VERSION 5.7 ;
BUSBITCHARS "[]" ;
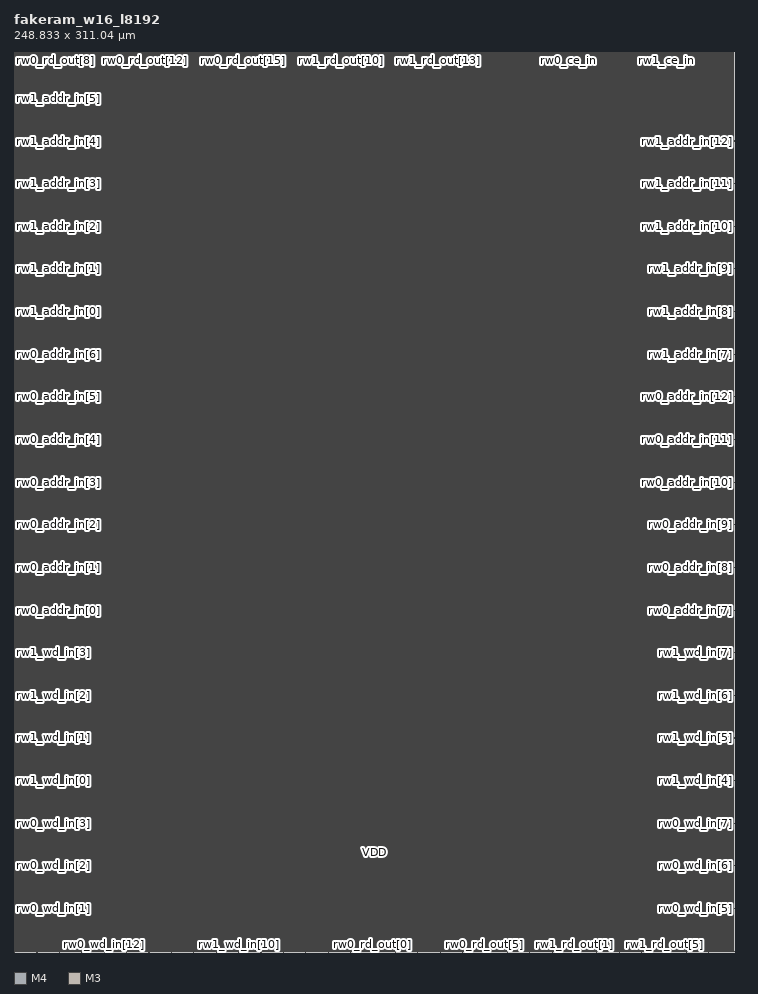
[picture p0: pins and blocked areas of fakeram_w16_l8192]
MACRO fakeram_w16_l8192
  FOREIGN fakeram_w16_l8192 0 0 ;
  SYMMETRY X Y R90 ;
  SIZE 248.833 BY 311.040 ;
  CLASS BLOCK ;
  PIN rw0_wd_in[0]
    DIRECTION INPUT ;
    USE SIGNAL ;
    SHAPE ABUTMENT ;
    PORT
      LAYER M4 ;
      RECT 0.000 0.276 0.072 0.300 ;
    END
  END rw0_wd_in[0]
  PIN rw0_wd_in[1]
    DIRECTION INPUT ;
    USE SIGNAL ;
    SHAPE ABUTMENT ;
    PORT
      LAYER M4 ;
      RECT 0.000 15.012 0.072 15.036 ;
    END
  END rw0_wd_in[1]
  PIN rw0_wd_in[2]
    DIRECTION INPUT ;
    USE SIGNAL ;
    SHAPE ABUTMENT ;
    PORT
      LAYER M4 ;
      RECT 0.000 29.748 0.072 29.772 ;
    END
  END rw0_wd_in[2]
  PIN rw0_wd_in[3]
    DIRECTION INPUT ;
    USE SIGNAL ;
    SHAPE ABUTMENT ;
    PORT
      LAYER M4 ;
      RECT 0.000 44.484 0.072 44.508 ;
    END
  END rw0_wd_in[3]
  PIN rw0_wd_in[4]
    DIRECTION INPUT ;
    USE SIGNAL ;
    SHAPE ABUTMENT ;
    PORT
      LAYER M4 ;
      RECT 248.761 0.276 248.833 0.300 ;
    END
  END rw0_wd_in[4]
  PIN rw0_wd_in[5]
    DIRECTION INPUT ;
    USE SIGNAL ;
    SHAPE ABUTMENT ;
    PORT
      LAYER M4 ;
      RECT 248.761 15.012 248.833 15.036 ;
    END
  END rw0_wd_in[5]
  PIN rw0_wd_in[6]
    DIRECTION INPUT ;
    USE SIGNAL ;
    SHAPE ABUTMENT ;
    PORT
      LAYER M4 ;
      RECT 248.761 29.748 248.833 29.772 ;
    END
  END rw0_wd_in[6]
  PIN rw0_wd_in[7]
    DIRECTION INPUT ;
    USE SIGNAL ;
    SHAPE ABUTMENT ;
    PORT
      LAYER M4 ;
      RECT 248.761 44.484 248.833 44.508 ;
    END
  END rw0_wd_in[7]
  PIN rw0_wd_in[8]
    DIRECTION INPUT ;
    USE SIGNAL ;
    SHAPE ABUTMENT ;
    PORT
      LAYER M3 ;
      RECT 0.207 0.000 0.225 0.054 ;
    END
  END rw0_wd_in[8]
  PIN rw0_wd_in[9]
    DIRECTION INPUT ;
    USE SIGNAL ;
    SHAPE ABUTMENT ;
    PORT
      LAYER M3 ;
      RECT 7.947 0.000 7.965 0.054 ;
    END
  END rw0_wd_in[9]
  PIN rw0_wd_in[10]
    DIRECTION INPUT ;
    USE SIGNAL ;
    SHAPE ABUTMENT ;
    PORT
      LAYER M3 ;
      RECT 15.687 0.000 15.705 0.054 ;
    END
  END rw0_wd_in[10]
  PIN rw0_wd_in[11]
    DIRECTION INPUT ;
    USE SIGNAL ;
    SHAPE ABUTMENT ;
    PORT
      LAYER M3 ;
      RECT 23.427 0.000 23.445 0.054 ;
    END
  END rw0_wd_in[11]
  PIN rw0_wd_in[12]
    DIRECTION INPUT ;
    USE SIGNAL ;
    SHAPE ABUTMENT ;
    PORT
      LAYER M3 ;
      RECT 31.167 0.000 31.185 0.054 ;
    END
  END rw0_wd_in[12]
  PIN rw0_wd_in[13]
    DIRECTION INPUT ;
    USE SIGNAL ;
    SHAPE ABUTMENT ;
    PORT
      LAYER M3 ;
      RECT 38.907 0.000 38.925 0.054 ;
    END
  END rw0_wd_in[13]
  PIN rw0_wd_in[14]
    DIRECTION INPUT ;
    USE SIGNAL ;
    SHAPE ABUTMENT ;
    PORT
      LAYER M3 ;
      RECT 46.647 0.000 46.665 0.054 ;
    END
  END rw0_wd_in[14]
  PIN rw0_wd_in[15]
    DIRECTION INPUT ;
    USE SIGNAL ;
    SHAPE ABUTMENT ;
    PORT
      LAYER M3 ;
      RECT 54.387 0.000 54.405 0.054 ;
    END
  END rw0_wd_in[15]
  PIN rw1_wd_in[0]
    DIRECTION INPUT ;
    USE SIGNAL ;
    SHAPE ABUTMENT ;
    PORT
      LAYER M4 ;
      RECT 0.000 59.220 0.072 59.244 ;
    END
  END rw1_wd_in[0]
  PIN rw1_wd_in[1]
    DIRECTION INPUT ;
    USE SIGNAL ;
    SHAPE ABUTMENT ;
    PORT
      LAYER M4 ;
      RECT 0.000 73.956 0.072 73.980 ;
    END
  END rw1_wd_in[1]
  PIN rw1_wd_in[2]
    DIRECTION INPUT ;
    USE SIGNAL ;
    SHAPE ABUTMENT ;
    PORT
      LAYER M4 ;
      RECT 0.000 88.692 0.072 88.716 ;
    END
  END rw1_wd_in[2]
  PIN rw1_wd_in[3]
    DIRECTION INPUT ;
    USE SIGNAL ;
    SHAPE ABUTMENT ;
    PORT
      LAYER M4 ;
      RECT 0.000 103.428 0.072 103.452 ;
    END
  END rw1_wd_in[3]
  PIN rw1_wd_in[4]
    DIRECTION INPUT ;
    USE SIGNAL ;
    SHAPE ABUTMENT ;
    PORT
      LAYER M4 ;
      RECT 248.761 59.220 248.833 59.244 ;
    END
  END rw1_wd_in[4]
  PIN rw1_wd_in[5]
    DIRECTION INPUT ;
    USE SIGNAL ;
    SHAPE ABUTMENT ;
    PORT
      LAYER M4 ;
      RECT 248.761 73.956 248.833 73.980 ;
    END
  END rw1_wd_in[5]
  PIN rw1_wd_in[6]
    DIRECTION INPUT ;
    USE SIGNAL ;
    SHAPE ABUTMENT ;
    PORT
      LAYER M4 ;
      RECT 248.761 88.692 248.833 88.716 ;
    END
  END rw1_wd_in[6]
  PIN rw1_wd_in[7]
    DIRECTION INPUT ;
    USE SIGNAL ;
    SHAPE ABUTMENT ;
    PORT
      LAYER M4 ;
      RECT 248.761 103.428 248.833 103.452 ;
    END
  END rw1_wd_in[7]
  PIN rw1_wd_in[8]
    DIRECTION INPUT ;
    USE SIGNAL ;
    SHAPE ABUTMENT ;
    PORT
      LAYER M3 ;
      RECT 62.127 0.000 62.145 0.054 ;
    END
  END rw1_wd_in[8]
  PIN rw1_wd_in[9]
    DIRECTION INPUT ;
    USE SIGNAL ;
    SHAPE ABUTMENT ;
    PORT
      LAYER M3 ;
      RECT 69.867 0.000 69.885 0.054 ;
    END
  END rw1_wd_in[9]
  PIN rw1_wd_in[10]
    DIRECTION INPUT ;
    USE SIGNAL ;
    SHAPE ABUTMENT ;
    PORT
      LAYER M3 ;
      RECT 77.607 0.000 77.625 0.054 ;
    END
  END rw1_wd_in[10]
  PIN rw1_wd_in[11]
    DIRECTION INPUT ;
    USE SIGNAL ;
    SHAPE ABUTMENT ;
    PORT
      LAYER M3 ;
      RECT 85.347 0.000 85.365 0.054 ;
    END
  END rw1_wd_in[11]
  PIN rw1_wd_in[12]
    DIRECTION INPUT ;
    USE SIGNAL ;
    SHAPE ABUTMENT ;
    PORT
      LAYER M3 ;
      RECT 93.087 0.000 93.105 0.054 ;
    END
  END rw1_wd_in[12]
  PIN rw1_wd_in[13]
    DIRECTION INPUT ;
    USE SIGNAL ;
    SHAPE ABUTMENT ;
    PORT
      LAYER M3 ;
      RECT 100.827 0.000 100.845 0.054 ;
    END
  END rw1_wd_in[13]
  PIN rw1_wd_in[14]
    DIRECTION INPUT ;
    USE SIGNAL ;
    SHAPE ABUTMENT ;
    PORT
      LAYER M3 ;
      RECT 108.567 0.000 108.585 0.054 ;
    END
  END rw1_wd_in[14]
  PIN rw1_wd_in[15]
    DIRECTION INPUT ;
    USE SIGNAL ;
    SHAPE ABUTMENT ;
    PORT
      LAYER M3 ;
      RECT 116.307 0.000 116.325 0.054 ;
    END
  END rw1_wd_in[15]
  PIN rw0_rd_out[0]
    DIRECTION OUTPUT ;
    USE SIGNAL ;
    SHAPE ABUTMENT ;
    PORT
      LAYER M3 ;
      RECT 124.047 0.000 124.065 0.054 ;
    END
  END rw0_rd_out[0]
  PIN rw0_rd_out[1]
    DIRECTION OUTPUT ;
    USE SIGNAL ;
    SHAPE ABUTMENT ;
    PORT
      LAYER M3 ;
      RECT 131.787 0.000 131.805 0.054 ;
    END
  END rw0_rd_out[1]
  PIN rw0_rd_out[2]
    DIRECTION OUTPUT ;
    USE SIGNAL ;
    SHAPE ABUTMENT ;
    PORT
      LAYER M3 ;
      RECT 139.527 0.000 139.545 0.054 ;
    END
  END rw0_rd_out[2]
  PIN rw0_rd_out[3]
    DIRECTION OUTPUT ;
    USE SIGNAL ;
    SHAPE ABUTMENT ;
    PORT
      LAYER M3 ;
      RECT 147.267 0.000 147.285 0.054 ;
    END
  END rw0_rd_out[3]
  PIN rw0_rd_out[4]
    DIRECTION OUTPUT ;
    USE SIGNAL ;
    SHAPE ABUTMENT ;
    PORT
      LAYER M3 ;
      RECT 155.007 0.000 155.025 0.054 ;
    END
  END rw0_rd_out[4]
  PIN rw0_rd_out[5]
    DIRECTION OUTPUT ;
    USE SIGNAL ;
    SHAPE ABUTMENT ;
    PORT
      LAYER M3 ;
      RECT 162.747 0.000 162.765 0.054 ;
    END
  END rw0_rd_out[5]
  PIN rw0_rd_out[6]
    DIRECTION OUTPUT ;
    USE SIGNAL ;
    SHAPE ABUTMENT ;
    PORT
      LAYER M3 ;
      RECT 170.487 0.000 170.505 0.054 ;
    END
  END rw0_rd_out[6]
  PIN rw0_rd_out[7]
    DIRECTION OUTPUT ;
    USE SIGNAL ;
    SHAPE ABUTMENT ;
    PORT
      LAYER M3 ;
      RECT 178.227 0.000 178.245 0.054 ;
    END
  END rw0_rd_out[7]
  PIN rw0_rd_out[8]
    DIRECTION OUTPUT ;
    USE SIGNAL ;
    SHAPE ABUTMENT ;
    PORT
      LAYER M3 ;
      RECT 0.207 310.986 0.225 311.040 ;
    END
  END rw0_rd_out[8]
  PIN rw0_rd_out[9]
    DIRECTION OUTPUT ;
    USE SIGNAL ;
    SHAPE ABUTMENT ;
    PORT
      LAYER M3 ;
      RECT 11.475 310.986 11.493 311.040 ;
    END
  END rw0_rd_out[9]
  PIN rw0_rd_out[10]
    DIRECTION OUTPUT ;
    USE SIGNAL ;
    SHAPE ABUTMENT ;
    PORT
      LAYER M3 ;
      RECT 22.743 310.986 22.761 311.040 ;
    END
  END rw0_rd_out[10]
  PIN rw0_rd_out[11]
    DIRECTION OUTPUT ;
    USE SIGNAL ;
    SHAPE ABUTMENT ;
    PORT
      LAYER M3 ;
      RECT 34.011 310.986 34.029 311.040 ;
    END
  END rw0_rd_out[11]
  PIN rw0_rd_out[12]
    DIRECTION OUTPUT ;
    USE SIGNAL ;
    SHAPE ABUTMENT ;
    PORT
      LAYER M3 ;
      RECT 45.279 310.986 45.297 311.040 ;
    END
  END rw0_rd_out[12]
  PIN rw0_rd_out[13]
    DIRECTION OUTPUT ;
    USE SIGNAL ;
    SHAPE ABUTMENT ;
    PORT
      LAYER M3 ;
      RECT 56.547 310.986 56.565 311.040 ;
    END
  END rw0_rd_out[13]
  PIN rw0_rd_out[14]
    DIRECTION OUTPUT ;
    USE SIGNAL ;
    SHAPE ABUTMENT ;
    PORT
      LAYER M3 ;
      RECT 67.815 310.986 67.833 311.040 ;
    END
  END rw0_rd_out[14]
  PIN rw0_rd_out[15]
    DIRECTION OUTPUT ;
    USE SIGNAL ;
    SHAPE ABUTMENT ;
    PORT
      LAYER M3 ;
      RECT 79.083 310.986 79.101 311.040 ;
    END
  END rw0_rd_out[15]
  PIN rw1_rd_out[0]
    DIRECTION OUTPUT ;
    USE SIGNAL ;
    SHAPE ABUTMENT ;
    PORT
      LAYER M3 ;
      RECT 185.967 0.000 185.985 0.054 ;
    END
  END rw1_rd_out[0]
  PIN rw1_rd_out[1]
    DIRECTION OUTPUT ;
    USE SIGNAL ;
    SHAPE ABUTMENT ;
    PORT
      LAYER M3 ;
      RECT 193.707 0.000 193.725 0.054 ;
    END
  END rw1_rd_out[1]
  PIN rw1_rd_out[2]
    DIRECTION OUTPUT ;
    USE SIGNAL ;
    SHAPE ABUTMENT ;
    PORT
      LAYER M3 ;
      RECT 201.447 0.000 201.465 0.054 ;
    END
  END rw1_rd_out[2]
  PIN rw1_rd_out[3]
    DIRECTION OUTPUT ;
    USE SIGNAL ;
    SHAPE ABUTMENT ;
    PORT
      LAYER M3 ;
      RECT 209.187 0.000 209.205 0.054 ;
    END
  END rw1_rd_out[3]
  PIN rw1_rd_out[4]
    DIRECTION OUTPUT ;
    USE SIGNAL ;
    SHAPE ABUTMENT ;
    PORT
      LAYER M3 ;
      RECT 216.927 0.000 216.945 0.054 ;
    END
  END rw1_rd_out[4]
  PIN rw1_rd_out[5]
    DIRECTION OUTPUT ;
    USE SIGNAL ;
    SHAPE ABUTMENT ;
    PORT
      LAYER M3 ;
      RECT 224.667 0.000 224.685 0.054 ;
    END
  END rw1_rd_out[5]
  PIN rw1_rd_out[6]
    DIRECTION OUTPUT ;
    USE SIGNAL ;
    SHAPE ABUTMENT ;
    PORT
      LAYER M3 ;
      RECT 232.407 0.000 232.425 0.054 ;
    END
  END rw1_rd_out[6]
  PIN rw1_rd_out[7]
    DIRECTION OUTPUT ;
    USE SIGNAL ;
    SHAPE ABUTMENT ;
    PORT
      LAYER M3 ;
      RECT 240.147 0.000 240.165 0.054 ;
    END
  END rw1_rd_out[7]
  PIN rw1_rd_out[8]
    DIRECTION OUTPUT ;
    USE SIGNAL ;
    SHAPE ABUTMENT ;
    PORT
      LAYER M3 ;
      RECT 90.351 310.986 90.369 311.040 ;
    END
  END rw1_rd_out[8]
  PIN rw1_rd_out[9]
    DIRECTION OUTPUT ;
    USE SIGNAL ;
    SHAPE ABUTMENT ;
    PORT
      LAYER M3 ;
      RECT 101.619 310.986 101.637 311.040 ;
    END
  END rw1_rd_out[9]
  PIN rw1_rd_out[10]
    DIRECTION OUTPUT ;
    USE SIGNAL ;
    SHAPE ABUTMENT ;
    PORT
      LAYER M3 ;
      RECT 112.887 310.986 112.905 311.040 ;
    END
  END rw1_rd_out[10]
  PIN rw1_rd_out[11]
    DIRECTION OUTPUT ;
    USE SIGNAL ;
    SHAPE ABUTMENT ;
    PORT
      LAYER M3 ;
      RECT 124.155 310.986 124.173 311.040 ;
    END
  END rw1_rd_out[11]
  PIN rw1_rd_out[12]
    DIRECTION OUTPUT ;
    USE SIGNAL ;
    SHAPE ABUTMENT ;
    PORT
      LAYER M3 ;
      RECT 135.423 310.986 135.441 311.040 ;
    END
  END rw1_rd_out[12]
  PIN rw1_rd_out[13]
    DIRECTION OUTPUT ;
    USE SIGNAL ;
    SHAPE ABUTMENT ;
    PORT
      LAYER M3 ;
      RECT 146.691 310.986 146.709 311.040 ;
    END
  END rw1_rd_out[13]
  PIN rw1_rd_out[14]
    DIRECTION OUTPUT ;
    USE SIGNAL ;
    SHAPE ABUTMENT ;
    PORT
      LAYER M3 ;
      RECT 157.959 310.986 157.977 311.040 ;
    END
  END rw1_rd_out[14]
  PIN rw1_rd_out[15]
    DIRECTION OUTPUT ;
    USE SIGNAL ;
    SHAPE ABUTMENT ;
    PORT
      LAYER M3 ;
      RECT 169.227 310.986 169.245 311.040 ;
    END
  END rw1_rd_out[15]
  PIN rw0_addr_in[0]
    DIRECTION INPUT ;
    USE SIGNAL ;
    SHAPE ABUTMENT ;
    PORT
      LAYER M4 ;
      RECT 0.000 118.164 0.072 118.188 ;
    END
  END rw0_addr_in[0]
  PIN rw0_addr_in[1]
    DIRECTION INPUT ;
    USE SIGNAL ;
    SHAPE ABUTMENT ;
    PORT
      LAYER M4 ;
      RECT 0.000 132.900 0.072 132.924 ;
    END
  END rw0_addr_in[1]
  PIN rw0_addr_in[2]
    DIRECTION INPUT ;
    USE SIGNAL ;
    SHAPE ABUTMENT ;
    PORT
      LAYER M4 ;
      RECT 0.000 147.636 0.072 147.660 ;
    END
  END rw0_addr_in[2]
  PIN rw0_addr_in[3]
    DIRECTION INPUT ;
    USE SIGNAL ;
    SHAPE ABUTMENT ;
    PORT
      LAYER M4 ;
      RECT 0.000 162.372 0.072 162.396 ;
    END
  END rw0_addr_in[3]
  PIN rw0_addr_in[4]
    DIRECTION INPUT ;
    USE SIGNAL ;
    SHAPE ABUTMENT ;
    PORT
      LAYER M4 ;
      RECT 0.000 177.108 0.072 177.132 ;
    END
  END rw0_addr_in[4]
  PIN rw0_addr_in[5]
    DIRECTION INPUT ;
    USE SIGNAL ;
    SHAPE ABUTMENT ;
    PORT
      LAYER M4 ;
      RECT 0.000 191.844 0.072 191.868 ;
    END
  END rw0_addr_in[5]
  PIN rw0_addr_in[6]
    DIRECTION INPUT ;
    USE SIGNAL ;
    SHAPE ABUTMENT ;
    PORT
      LAYER M4 ;
      RECT 0.000 206.580 0.072 206.604 ;
    END
  END rw0_addr_in[6]
  PIN rw0_addr_in[7]
    DIRECTION INPUT ;
    USE SIGNAL ;
    SHAPE ABUTMENT ;
    PORT
      LAYER M4 ;
      RECT 248.761 118.164 248.833 118.188 ;
    END
  END rw0_addr_in[7]
  PIN rw0_addr_in[8]
    DIRECTION INPUT ;
    USE SIGNAL ;
    SHAPE ABUTMENT ;
    PORT
      LAYER M4 ;
      RECT 248.761 132.900 248.833 132.924 ;
    END
  END rw0_addr_in[8]
  PIN rw0_addr_in[9]
    DIRECTION INPUT ;
    USE SIGNAL ;
    SHAPE ABUTMENT ;
    PORT
      LAYER M4 ;
      RECT 248.761 147.636 248.833 147.660 ;
    END
  END rw0_addr_in[9]
  PIN rw0_addr_in[10]
    DIRECTION INPUT ;
    USE SIGNAL ;
    SHAPE ABUTMENT ;
    PORT
      LAYER M4 ;
      RECT 248.761 162.372 248.833 162.396 ;
    END
  END rw0_addr_in[10]
  PIN rw0_addr_in[11]
    DIRECTION INPUT ;
    USE SIGNAL ;
    SHAPE ABUTMENT ;
    PORT
      LAYER M4 ;
      RECT 248.761 177.108 248.833 177.132 ;
    END
  END rw0_addr_in[11]
  PIN rw0_addr_in[12]
    DIRECTION INPUT ;
    USE SIGNAL ;
    SHAPE ABUTMENT ;
    PORT
      LAYER M4 ;
      RECT 248.761 191.844 248.833 191.868 ;
    END
  END rw0_addr_in[12]
  PIN rw1_addr_in[0]
    DIRECTION INPUT ;
    USE SIGNAL ;
    SHAPE ABUTMENT ;
    PORT
      LAYER M4 ;
      RECT 0.000 221.316 0.072 221.340 ;
    END
  END rw1_addr_in[0]
  PIN rw1_addr_in[1]
    DIRECTION INPUT ;
    USE SIGNAL ;
    SHAPE ABUTMENT ;
    PORT
      LAYER M4 ;
      RECT 0.000 236.052 0.072 236.076 ;
    END
  END rw1_addr_in[1]
  PIN rw1_addr_in[2]
    DIRECTION INPUT ;
    USE SIGNAL ;
    SHAPE ABUTMENT ;
    PORT
      LAYER M4 ;
      RECT 0.000 250.788 0.072 250.812 ;
    END
  END rw1_addr_in[2]
  PIN rw1_addr_in[3]
    DIRECTION INPUT ;
    USE SIGNAL ;
    SHAPE ABUTMENT ;
    PORT
      LAYER M4 ;
      RECT 0.000 265.524 0.072 265.548 ;
    END
  END rw1_addr_in[3]
  PIN rw1_addr_in[4]
    DIRECTION INPUT ;
    USE SIGNAL ;
    SHAPE ABUTMENT ;
    PORT
      LAYER M4 ;
      RECT 0.000 280.260 0.072 280.284 ;
    END
  END rw1_addr_in[4]
  PIN rw1_addr_in[5]
    DIRECTION INPUT ;
    USE SIGNAL ;
    SHAPE ABUTMENT ;
    PORT
      LAYER M4 ;
      RECT 0.000 294.996 0.072 295.020 ;
    END
  END rw1_addr_in[5]
  PIN rw1_addr_in[6]
    DIRECTION INPUT ;
    USE SIGNAL ;
    SHAPE ABUTMENT ;
    PORT
      LAYER M4 ;
      RECT 0.000 309.732 0.072 309.756 ;
    END
  END rw1_addr_in[6]
  PIN rw1_addr_in[7]
    DIRECTION INPUT ;
    USE SIGNAL ;
    SHAPE ABUTMENT ;
    PORT
      LAYER M4 ;
      RECT 248.761 206.580 248.833 206.604 ;
    END
  END rw1_addr_in[7]
  PIN rw1_addr_in[8]
    DIRECTION INPUT ;
    USE SIGNAL ;
    SHAPE ABUTMENT ;
    PORT
      LAYER M4 ;
      RECT 248.761 221.316 248.833 221.340 ;
    END
  END rw1_addr_in[8]
  PIN rw1_addr_in[9]
    DIRECTION INPUT ;
    USE SIGNAL ;
    SHAPE ABUTMENT ;
    PORT
      LAYER M4 ;
      RECT 248.761 236.052 248.833 236.076 ;
    END
  END rw1_addr_in[9]
  PIN rw1_addr_in[10]
    DIRECTION INPUT ;
    USE SIGNAL ;
    SHAPE ABUTMENT ;
    PORT
      LAYER M4 ;
      RECT 248.761 250.788 248.833 250.812 ;
    END
  END rw1_addr_in[10]
  PIN rw1_addr_in[11]
    DIRECTION INPUT ;
    USE SIGNAL ;
    SHAPE ABUTMENT ;
    PORT
      LAYER M4 ;
      RECT 248.761 265.524 248.833 265.548 ;
    END
  END rw1_addr_in[11]
  PIN rw1_addr_in[12]
    DIRECTION INPUT ;
    USE SIGNAL ;
    SHAPE ABUTMENT ;
    PORT
      LAYER M4 ;
      RECT 248.761 280.260 248.833 280.284 ;
    END
  END rw1_addr_in[12]
  PIN rw0_we_in
    DIRECTION INPUT ;
    USE SIGNAL ;
    SHAPE ABUTMENT ;
    PORT
      LAYER M3 ;
      RECT 180.495 310.986 180.513 311.040 ;
    END
  END rw0_we_in
  PIN rw0_ce_in
    DIRECTION INPUT ;
    USE SIGNAL ;
    SHAPE ABUTMENT ;
    PORT
      LAYER M3 ;
      RECT 191.763 310.986 191.781 311.040 ;
    END
  END rw0_ce_in
  PIN rw0_clk
    DIRECTION INPUT ;
    USE SIGNAL ;
    SHAPE ABUTMENT ;
    PORT
      LAYER M3 ;
      RECT 203.031 310.986 203.049 311.040 ;
    END
  END rw0_clk
  PIN rw1_we_in
    DIRECTION INPUT ;
    USE SIGNAL ;
    SHAPE ABUTMENT ;
    PORT
      LAYER M3 ;
      RECT 214.299 310.986 214.317 311.040 ;
    END
  END rw1_we_in
  PIN rw1_ce_in
    DIRECTION INPUT ;
    USE SIGNAL ;
    SHAPE ABUTMENT ;
    PORT
      LAYER M3 ;
      RECT 225.567 310.986 225.585 311.040 ;
    END
  END rw1_ce_in
  PIN rw1_clk
    DIRECTION INPUT ;
    USE SIGNAL ;
    SHAPE ABUTMENT ;
    PORT
      LAYER M3 ;
      RECT 236.835 310.986 236.853 311.040 ;
    END
  END rw1_clk
  PIN VSS
    DIRECTION INOUT ;
    USE GROUND ;
    PORT
      LAYER M4 ;
      RECT 0.216 0.240 248.617 0.336 ;
      RECT 0.216 1.008 248.617 1.104 ;
      RECT 0.216 1.776 248.617 1.872 ;
      RECT 0.216 2.544 248.617 2.640 ;
      RECT 0.216 3.312 248.617 3.408 ;
      RECT 0.216 4.080 248.617 4.176 ;
      RECT 0.216 4.848 248.617 4.944 ;
      RECT 0.216 5.616 248.617 5.712 ;
      RECT 0.216 6.384 248.617 6.480 ;
      RECT 0.216 7.152 248.617 7.248 ;
      RECT 0.216 7.920 248.617 8.016 ;
      RECT 0.216 8.688 248.617 8.784 ;
      RECT 0.216 9.456 248.617 9.552 ;
      RECT 0.216 10.224 248.617 10.320 ;
      RECT 0.216 10.992 248.617 11.088 ;
      RECT 0.216 11.760 248.617 11.856 ;
      RECT 0.216 12.528 248.617 12.624 ;
      RECT 0.216 13.296 248.617 13.392 ;
      RECT 0.216 14.064 248.617 14.160 ;
      RECT 0.216 14.832 248.617 14.928 ;
      RECT 0.216 15.600 248.617 15.696 ;
      RECT 0.216 16.368 248.617 16.464 ;
      RECT 0.216 17.136 248.617 17.232 ;
      RECT 0.216 17.904 248.617 18.000 ;
      RECT 0.216 18.672 248.617 18.768 ;
      RECT 0.216 19.440 248.617 19.536 ;
      RECT 0.216 20.208 248.617 20.304 ;
      RECT 0.216 20.976 248.617 21.072 ;
      RECT 0.216 21.744 248.617 21.840 ;
      RECT 0.216 22.512 248.617 22.608 ;
      RECT 0.216 23.280 248.617 23.376 ;
      RECT 0.216 24.048 248.617 24.144 ;
      RECT 0.216 24.816 248.617 24.912 ;
      RECT 0.216 25.584 248.617 25.680 ;
      RECT 0.216 26.352 248.617 26.448 ;
      RECT 0.216 27.120 248.617 27.216 ;
      RECT 0.216 27.888 248.617 27.984 ;
      RECT 0.216 28.656 248.617 28.752 ;
      RECT 0.216 29.424 248.617 29.520 ;
      RECT 0.216 30.192 248.617 30.288 ;
      RECT 0.216 30.960 248.617 31.056 ;
      RECT 0.216 31.728 248.617 31.824 ;
      RECT 0.216 32.496 248.617 32.592 ;
      RECT 0.216 33.264 248.617 33.360 ;
      RECT 0.216 34.032 248.617 34.128 ;
      RECT 0.216 34.800 248.617 34.896 ;
      RECT 0.216 35.568 248.617 35.664 ;
      RECT 0.216 36.336 248.617 36.432 ;
      RECT 0.216 37.104 248.617 37.200 ;
      RECT 0.216 37.872 248.617 37.968 ;
      RECT 0.216 38.640 248.617 38.736 ;
      RECT 0.216 39.408 248.617 39.504 ;
      RECT 0.216 40.176 248.617 40.272 ;
      RECT 0.216 40.944 248.617 41.040 ;
      RECT 0.216 41.712 248.617 41.808 ;
      RECT 0.216 42.480 248.617 42.576 ;
      RECT 0.216 43.248 248.617 43.344 ;
      RECT 0.216 44.016 248.617 44.112 ;
      RECT 0.216 44.784 248.617 44.880 ;
      RECT 0.216 45.552 248.617 45.648 ;
      RECT 0.216 46.320 248.617 46.416 ;
      RECT 0.216 47.088 248.617 47.184 ;
      RECT 0.216 47.856 248.617 47.952 ;
      RECT 0.216 48.624 248.617 48.720 ;
      RECT 0.216 49.392 248.617 49.488 ;
      RECT 0.216 50.160 248.617 50.256 ;
      RECT 0.216 50.928 248.617 51.024 ;
      RECT 0.216 51.696 248.617 51.792 ;
      RECT 0.216 52.464 248.617 52.560 ;
      RECT 0.216 53.232 248.617 53.328 ;
      RECT 0.216 54.000 248.617 54.096 ;
      RECT 0.216 54.768 248.617 54.864 ;
      RECT 0.216 55.536 248.617 55.632 ;
      RECT 0.216 56.304 248.617 56.400 ;
      RECT 0.216 57.072 248.617 57.168 ;
      RECT 0.216 57.840 248.617 57.936 ;
      RECT 0.216 58.608 248.617 58.704 ;
      RECT 0.216 59.376 248.617 59.472 ;
      RECT 0.216 60.144 248.617 60.240 ;
      RECT 0.216 60.912 248.617 61.008 ;
      RECT 0.216 61.680 248.617 61.776 ;
      RECT 0.216 62.448 248.617 62.544 ;
      RECT 0.216 63.216 248.617 63.312 ;
      RECT 0.216 63.984 248.617 64.080 ;
      RECT 0.216 64.752 248.617 64.848 ;
      RECT 0.216 65.520 248.617 65.616 ;
      RECT 0.216 66.288 248.617 66.384 ;
      RECT 0.216 67.056 248.617 67.152 ;
      RECT 0.216 67.824 248.617 67.920 ;
      RECT 0.216 68.592 248.617 68.688 ;
      RECT 0.216 69.360 248.617 69.456 ;
      RECT 0.216 70.128 248.617 70.224 ;
      RECT 0.216 70.896 248.617 70.992 ;
      RECT 0.216 71.664 248.617 71.760 ;
      RECT 0.216 72.432 248.617 72.528 ;
      RECT 0.216 73.200 248.617 73.296 ;
      RECT 0.216 73.968 248.617 74.064 ;
      RECT 0.216 74.736 248.617 74.832 ;
      RECT 0.216 75.504 248.617 75.600 ;
      RECT 0.216 76.272 248.617 76.368 ;
      RECT 0.216 77.040 248.617 77.136 ;
      RECT 0.216 77.808 248.617 77.904 ;
      RECT 0.216 78.576 248.617 78.672 ;
      RECT 0.216 79.344 248.617 79.440 ;
      RECT 0.216 80.112 248.617 80.208 ;
      RECT 0.216 80.880 248.617 80.976 ;
      RECT 0.216 81.648 248.617 81.744 ;
      RECT 0.216 82.416 248.617 82.512 ;
      RECT 0.216 83.184 248.617 83.280 ;
      RECT 0.216 83.952 248.617 84.048 ;
      RECT 0.216 84.720 248.617 84.816 ;
      RECT 0.216 85.488 248.617 85.584 ;
      RECT 0.216 86.256 248.617 86.352 ;
      RECT 0.216 87.024 248.617 87.120 ;
      RECT 0.216 87.792 248.617 87.888 ;
      RECT 0.216 88.560 248.617 88.656 ;
      RECT 0.216 89.328 248.617 89.424 ;
      RECT 0.216 90.096 248.617 90.192 ;
      RECT 0.216 90.864 248.617 90.960 ;
      RECT 0.216 91.632 248.617 91.728 ;
      RECT 0.216 92.400 248.617 92.496 ;
      RECT 0.216 93.168 248.617 93.264 ;
      RECT 0.216 93.936 248.617 94.032 ;
      RECT 0.216 94.704 248.617 94.800 ;
      RECT 0.216 95.472 248.617 95.568 ;
      RECT 0.216 96.240 248.617 96.336 ;
      RECT 0.216 97.008 248.617 97.104 ;
      RECT 0.216 97.776 248.617 97.872 ;
      RECT 0.216 98.544 248.617 98.640 ;
      RECT 0.216 99.312 248.617 99.408 ;
      RECT 0.216 100.080 248.617 100.176 ;
      RECT 0.216 100.848 248.617 100.944 ;
      RECT 0.216 101.616 248.617 101.712 ;
      RECT 0.216 102.384 248.617 102.480 ;
      RECT 0.216 103.152 248.617 103.248 ;
      RECT 0.216 103.920 248.617 104.016 ;
      RECT 0.216 104.688 248.617 104.784 ;
      RECT 0.216 105.456 248.617 105.552 ;
      RECT 0.216 106.224 248.617 106.320 ;
      RECT 0.216 106.992 248.617 107.088 ;
      RECT 0.216 107.760 248.617 107.856 ;
      RECT 0.216 108.528 248.617 108.624 ;
      RECT 0.216 109.296 248.617 109.392 ;
      RECT 0.216 110.064 248.617 110.160 ;
      RECT 0.216 110.832 248.617 110.928 ;
      RECT 0.216 111.600 248.617 111.696 ;
      RECT 0.216 112.368 248.617 112.464 ;
      RECT 0.216 113.136 248.617 113.232 ;
      RECT 0.216 113.904 248.617 114.000 ;
      RECT 0.216 114.672 248.617 114.768 ;
      RECT 0.216 115.440 248.617 115.536 ;
      RECT 0.216 116.208 248.617 116.304 ;
      RECT 0.216 116.976 248.617 117.072 ;
      RECT 0.216 117.744 248.617 117.840 ;
      RECT 0.216 118.512 248.617 118.608 ;
      RECT 0.216 119.280 248.617 119.376 ;
      RECT 0.216 120.048 248.617 120.144 ;
      RECT 0.216 120.816 248.617 120.912 ;
      RECT 0.216 121.584 248.617 121.680 ;
      RECT 0.216 122.352 248.617 122.448 ;
      RECT 0.216 123.120 248.617 123.216 ;
      RECT 0.216 123.888 248.617 123.984 ;
      RECT 0.216 124.656 248.617 124.752 ;
      RECT 0.216 125.424 248.617 125.520 ;
      RECT 0.216 126.192 248.617 126.288 ;
      RECT 0.216 126.960 248.617 127.056 ;
      RECT 0.216 127.728 248.617 127.824 ;
      RECT 0.216 128.496 248.617 128.592 ;
      RECT 0.216 129.264 248.617 129.360 ;
      RECT 0.216 130.032 248.617 130.128 ;
      RECT 0.216 130.800 248.617 130.896 ;
      RECT 0.216 131.568 248.617 131.664 ;
      RECT 0.216 132.336 248.617 132.432 ;
      RECT 0.216 133.104 248.617 133.200 ;
      RECT 0.216 133.872 248.617 133.968 ;
      RECT 0.216 134.640 248.617 134.736 ;
      RECT 0.216 135.408 248.617 135.504 ;
      RECT 0.216 136.176 248.617 136.272 ;
      RECT 0.216 136.944 248.617 137.040 ;
      RECT 0.216 137.712 248.617 137.808 ;
      RECT 0.216 138.480 248.617 138.576 ;
      RECT 0.216 139.248 248.617 139.344 ;
      RECT 0.216 140.016 248.617 140.112 ;
      RECT 0.216 140.784 248.617 140.880 ;
      RECT 0.216 141.552 248.617 141.648 ;
      RECT 0.216 142.320 248.617 142.416 ;
      RECT 0.216 143.088 248.617 143.184 ;
      RECT 0.216 143.856 248.617 143.952 ;
      RECT 0.216 144.624 248.617 144.720 ;
      RECT 0.216 145.392 248.617 145.488 ;
      RECT 0.216 146.160 248.617 146.256 ;
      RECT 0.216 146.928 248.617 147.024 ;
      RECT 0.216 147.696 248.617 147.792 ;
      RECT 0.216 148.464 248.617 148.560 ;
      RECT 0.216 149.232 248.617 149.328 ;
      RECT 0.216 150.000 248.617 150.096 ;
      RECT 0.216 150.768 248.617 150.864 ;
      RECT 0.216 151.536 248.617 151.632 ;
      RECT 0.216 152.304 248.617 152.400 ;
      RECT 0.216 153.072 248.617 153.168 ;
      RECT 0.216 153.840 248.617 153.936 ;
      RECT 0.216 154.608 248.617 154.704 ;
      RECT 0.216 155.376 248.617 155.472 ;
      RECT 0.216 156.144 248.617 156.240 ;
      RECT 0.216 156.912 248.617 157.008 ;
      RECT 0.216 157.680 248.617 157.776 ;
      RECT 0.216 158.448 248.617 158.544 ;
      RECT 0.216 159.216 248.617 159.312 ;
      RECT 0.216 159.984 248.617 160.080 ;
      RECT 0.216 160.752 248.617 160.848 ;
      RECT 0.216 161.520 248.617 161.616 ;
      RECT 0.216 162.288 248.617 162.384 ;
      RECT 0.216 163.056 248.617 163.152 ;
      RECT 0.216 163.824 248.617 163.920 ;
      RECT 0.216 164.592 248.617 164.688 ;
      RECT 0.216 165.360 248.617 165.456 ;
      RECT 0.216 166.128 248.617 166.224 ;
      RECT 0.216 166.896 248.617 166.992 ;
      RECT 0.216 167.664 248.617 167.760 ;
      RECT 0.216 168.432 248.617 168.528 ;
      RECT 0.216 169.200 248.617 169.296 ;
      RECT 0.216 169.968 248.617 170.064 ;
      RECT 0.216 170.736 248.617 170.832 ;
      RECT 0.216 171.504 248.617 171.600 ;
      RECT 0.216 172.272 248.617 172.368 ;
      RECT 0.216 173.040 248.617 173.136 ;
      RECT 0.216 173.808 248.617 173.904 ;
      RECT 0.216 174.576 248.617 174.672 ;
      RECT 0.216 175.344 248.617 175.440 ;
      RECT 0.216 176.112 248.617 176.208 ;
      RECT 0.216 176.880 248.617 176.976 ;
      RECT 0.216 177.648 248.617 177.744 ;
      RECT 0.216 178.416 248.617 178.512 ;
      RECT 0.216 179.184 248.617 179.280 ;
      RECT 0.216 179.952 248.617 180.048 ;
      RECT 0.216 180.720 248.617 180.816 ;
      RECT 0.216 181.488 248.617 181.584 ;
      RECT 0.216 182.256 248.617 182.352 ;
      RECT 0.216 183.024 248.617 183.120 ;
      RECT 0.216 183.792 248.617 183.888 ;
      RECT 0.216 184.560 248.617 184.656 ;
      RECT 0.216 185.328 248.617 185.424 ;
      RECT 0.216 186.096 248.617 186.192 ;
      RECT 0.216 186.864 248.617 186.960 ;
      RECT 0.216 187.632 248.617 187.728 ;
      RECT 0.216 188.400 248.617 188.496 ;
      RECT 0.216 189.168 248.617 189.264 ;
      RECT 0.216 189.936 248.617 190.032 ;
      RECT 0.216 190.704 248.617 190.800 ;
      RECT 0.216 191.472 248.617 191.568 ;
      RECT 0.216 192.240 248.617 192.336 ;
      RECT 0.216 193.008 248.617 193.104 ;
      RECT 0.216 193.776 248.617 193.872 ;
      RECT 0.216 194.544 248.617 194.640 ;
      RECT 0.216 195.312 248.617 195.408 ;
      RECT 0.216 196.080 248.617 196.176 ;
      RECT 0.216 196.848 248.617 196.944 ;
      RECT 0.216 197.616 248.617 197.712 ;
      RECT 0.216 198.384 248.617 198.480 ;
      RECT 0.216 199.152 248.617 199.248 ;
      RECT 0.216 199.920 248.617 200.016 ;
      RECT 0.216 200.688 248.617 200.784 ;
      RECT 0.216 201.456 248.617 201.552 ;
      RECT 0.216 202.224 248.617 202.320 ;
      RECT 0.216 202.992 248.617 203.088 ;
      RECT 0.216 203.760 248.617 203.856 ;
      RECT 0.216 204.528 248.617 204.624 ;
      RECT 0.216 205.296 248.617 205.392 ;
      RECT 0.216 206.064 248.617 206.160 ;
      RECT 0.216 206.832 248.617 206.928 ;
      RECT 0.216 207.600 248.617 207.696 ;
      RECT 0.216 208.368 248.617 208.464 ;
      RECT 0.216 209.136 248.617 209.232 ;
      RECT 0.216 209.904 248.617 210.000 ;
      RECT 0.216 210.672 248.617 210.768 ;
      RECT 0.216 211.440 248.617 211.536 ;
      RECT 0.216 212.208 248.617 212.304 ;
      RECT 0.216 212.976 248.617 213.072 ;
      RECT 0.216 213.744 248.617 213.840 ;
      RECT 0.216 214.512 248.617 214.608 ;
      RECT 0.216 215.280 248.617 215.376 ;
      RECT 0.216 216.048 248.617 216.144 ;
      RECT 0.216 216.816 248.617 216.912 ;
      RECT 0.216 217.584 248.617 217.680 ;
      RECT 0.216 218.352 248.617 218.448 ;
      RECT 0.216 219.120 248.617 219.216 ;
      RECT 0.216 219.888 248.617 219.984 ;
      RECT 0.216 220.656 248.617 220.752 ;
      RECT 0.216 221.424 248.617 221.520 ;
      RECT 0.216 222.192 248.617 222.288 ;
      RECT 0.216 222.960 248.617 223.056 ;
      RECT 0.216 223.728 248.617 223.824 ;
      RECT 0.216 224.496 248.617 224.592 ;
      RECT 0.216 225.264 248.617 225.360 ;
      RECT 0.216 226.032 248.617 226.128 ;
      RECT 0.216 226.800 248.617 226.896 ;
      RECT 0.216 227.568 248.617 227.664 ;
      RECT 0.216 228.336 248.617 228.432 ;
      RECT 0.216 229.104 248.617 229.200 ;
      RECT 0.216 229.872 248.617 229.968 ;
      RECT 0.216 230.640 248.617 230.736 ;
      RECT 0.216 231.408 248.617 231.504 ;
      RECT 0.216 232.176 248.617 232.272 ;
      RECT 0.216 232.944 248.617 233.040 ;
      RECT 0.216 233.712 248.617 233.808 ;
      RECT 0.216 234.480 248.617 234.576 ;
      RECT 0.216 235.248 248.617 235.344 ;
      RECT 0.216 236.016 248.617 236.112 ;
      RECT 0.216 236.784 248.617 236.880 ;
      RECT 0.216 237.552 248.617 237.648 ;
      RECT 0.216 238.320 248.617 238.416 ;
      RECT 0.216 239.088 248.617 239.184 ;
      RECT 0.216 239.856 248.617 239.952 ;
      RECT 0.216 240.624 248.617 240.720 ;
      RECT 0.216 241.392 248.617 241.488 ;
      RECT 0.216 242.160 248.617 242.256 ;
      RECT 0.216 242.928 248.617 243.024 ;
      RECT 0.216 243.696 248.617 243.792 ;
      RECT 0.216 244.464 248.617 244.560 ;
      RECT 0.216 245.232 248.617 245.328 ;
      RECT 0.216 246.000 248.617 246.096 ;
      RECT 0.216 246.768 248.617 246.864 ;
      RECT 0.216 247.536 248.617 247.632 ;
      RECT 0.216 248.304 248.617 248.400 ;
      RECT 0.216 249.072 248.617 249.168 ;
      RECT 0.216 249.840 248.617 249.936 ;
      RECT 0.216 250.608 248.617 250.704 ;
      RECT 0.216 251.376 248.617 251.472 ;
      RECT 0.216 252.144 248.617 252.240 ;
      RECT 0.216 252.912 248.617 253.008 ;
      RECT 0.216 253.680 248.617 253.776 ;
      RECT 0.216 254.448 248.617 254.544 ;
      RECT 0.216 255.216 248.617 255.312 ;
      RECT 0.216 255.984 248.617 256.080 ;
      RECT 0.216 256.752 248.617 256.848 ;
      RECT 0.216 257.520 248.617 257.616 ;
      RECT 0.216 258.288 248.617 258.384 ;
      RECT 0.216 259.056 248.617 259.152 ;
      RECT 0.216 259.824 248.617 259.920 ;
      RECT 0.216 260.592 248.617 260.688 ;
      RECT 0.216 261.360 248.617 261.456 ;
      RECT 0.216 262.128 248.617 262.224 ;
      RECT 0.216 262.896 248.617 262.992 ;
      RECT 0.216 263.664 248.617 263.760 ;
      RECT 0.216 264.432 248.617 264.528 ;
      RECT 0.216 265.200 248.617 265.296 ;
      RECT 0.216 265.968 248.617 266.064 ;
      RECT 0.216 266.736 248.617 266.832 ;
      RECT 0.216 267.504 248.617 267.600 ;
      RECT 0.216 268.272 248.617 268.368 ;
      RECT 0.216 269.040 248.617 269.136 ;
      RECT 0.216 269.808 248.617 269.904 ;
      RECT 0.216 270.576 248.617 270.672 ;
      RECT 0.216 271.344 248.617 271.440 ;
      RECT 0.216 272.112 248.617 272.208 ;
      RECT 0.216 272.880 248.617 272.976 ;
      RECT 0.216 273.648 248.617 273.744 ;
      RECT 0.216 274.416 248.617 274.512 ;
      RECT 0.216 275.184 248.617 275.280 ;
      RECT 0.216 275.952 248.617 276.048 ;
      RECT 0.216 276.720 248.617 276.816 ;
      RECT 0.216 277.488 248.617 277.584 ;
      RECT 0.216 278.256 248.617 278.352 ;
      RECT 0.216 279.024 248.617 279.120 ;
      RECT 0.216 279.792 248.617 279.888 ;
      RECT 0.216 280.560 248.617 280.656 ;
      RECT 0.216 281.328 248.617 281.424 ;
      RECT 0.216 282.096 248.617 282.192 ;
      RECT 0.216 282.864 248.617 282.960 ;
      RECT 0.216 283.632 248.617 283.728 ;
      RECT 0.216 284.400 248.617 284.496 ;
      RECT 0.216 285.168 248.617 285.264 ;
      RECT 0.216 285.936 248.617 286.032 ;
      RECT 0.216 286.704 248.617 286.800 ;
      RECT 0.216 287.472 248.617 287.568 ;
      RECT 0.216 288.240 248.617 288.336 ;
      RECT 0.216 289.008 248.617 289.104 ;
      RECT 0.216 289.776 248.617 289.872 ;
      RECT 0.216 290.544 248.617 290.640 ;
      RECT 0.216 291.312 248.617 291.408 ;
      RECT 0.216 292.080 248.617 292.176 ;
      RECT 0.216 292.848 248.617 292.944 ;
      RECT 0.216 293.616 248.617 293.712 ;
      RECT 0.216 294.384 248.617 294.480 ;
      RECT 0.216 295.152 248.617 295.248 ;
      RECT 0.216 295.920 248.617 296.016 ;
      RECT 0.216 296.688 248.617 296.784 ;
      RECT 0.216 297.456 248.617 297.552 ;
      RECT 0.216 298.224 248.617 298.320 ;
      RECT 0.216 298.992 248.617 299.088 ;
      RECT 0.216 299.760 248.617 299.856 ;
      RECT 0.216 300.528 248.617 300.624 ;
      RECT 0.216 301.296 248.617 301.392 ;
      RECT 0.216 302.064 248.617 302.160 ;
      RECT 0.216 302.832 248.617 302.928 ;
      RECT 0.216 303.600 248.617 303.696 ;
      RECT 0.216 304.368 248.617 304.464 ;
      RECT 0.216 305.136 248.617 305.232 ;
      RECT 0.216 305.904 248.617 306.000 ;
      RECT 0.216 306.672 248.617 306.768 ;
      RECT 0.216 307.440 248.617 307.536 ;
      RECT 0.216 308.208 248.617 308.304 ;
      RECT 0.216 308.976 248.617 309.072 ;
      RECT 0.216 309.744 248.617 309.840 ;
      RECT 0.216 310.512 248.617 310.608 ;
    END
  END VSS
  PIN VDD
    DIRECTION INOUT ;
    USE POWER ;
    PORT
      LAYER M4 ;
      RECT 0.216 0.624 248.617 0.720 ;
      RECT 0.216 1.392 248.617 1.488 ;
      RECT 0.216 2.160 248.617 2.256 ;
      RECT 0.216 2.928 248.617 3.024 ;
      RECT 0.216 3.696 248.617 3.792 ;
      RECT 0.216 4.464 248.617 4.560 ;
      RECT 0.216 5.232 248.617 5.328 ;
      RECT 0.216 6.000 248.617 6.096 ;
      RECT 0.216 6.768 248.617 6.864 ;
      RECT 0.216 7.536 248.617 7.632 ;
      RECT 0.216 8.304 248.617 8.400 ;
      RECT 0.216 9.072 248.617 9.168 ;
      RECT 0.216 9.840 248.617 9.936 ;
      RECT 0.216 10.608 248.617 10.704 ;
      RECT 0.216 11.376 248.617 11.472 ;
      RECT 0.216 12.144 248.617 12.240 ;
      RECT 0.216 12.912 248.617 13.008 ;
      RECT 0.216 13.680 248.617 13.776 ;
      RECT 0.216 14.448 248.617 14.544 ;
      RECT 0.216 15.216 248.617 15.312 ;
      RECT 0.216 15.984 248.617 16.080 ;
      RECT 0.216 16.752 248.617 16.848 ;
      RECT 0.216 17.520 248.617 17.616 ;
      RECT 0.216 18.288 248.617 18.384 ;
      RECT 0.216 19.056 248.617 19.152 ;
      RECT 0.216 19.824 248.617 19.920 ;
      RECT 0.216 20.592 248.617 20.688 ;
      RECT 0.216 21.360 248.617 21.456 ;
      RECT 0.216 22.128 248.617 22.224 ;
      RECT 0.216 22.896 248.617 22.992 ;
      RECT 0.216 23.664 248.617 23.760 ;
      RECT 0.216 24.432 248.617 24.528 ;
      RECT 0.216 25.200 248.617 25.296 ;
      RECT 0.216 25.968 248.617 26.064 ;
      RECT 0.216 26.736 248.617 26.832 ;
      RECT 0.216 27.504 248.617 27.600 ;
      RECT 0.216 28.272 248.617 28.368 ;
      RECT 0.216 29.040 248.617 29.136 ;
      RECT 0.216 29.808 248.617 29.904 ;
      RECT 0.216 30.576 248.617 30.672 ;
      RECT 0.216 31.344 248.617 31.440 ;
      RECT 0.216 32.112 248.617 32.208 ;
      RECT 0.216 32.880 248.617 32.976 ;
      RECT 0.216 33.648 248.617 33.744 ;
      RECT 0.216 34.416 248.617 34.512 ;
      RECT 0.216 35.184 248.617 35.280 ;
      RECT 0.216 35.952 248.617 36.048 ;
      RECT 0.216 36.720 248.617 36.816 ;
      RECT 0.216 37.488 248.617 37.584 ;
      RECT 0.216 38.256 248.617 38.352 ;
      RECT 0.216 39.024 248.617 39.120 ;
      RECT 0.216 39.792 248.617 39.888 ;
      RECT 0.216 40.560 248.617 40.656 ;
      RECT 0.216 41.328 248.617 41.424 ;
      RECT 0.216 42.096 248.617 42.192 ;
      RECT 0.216 42.864 248.617 42.960 ;
      RECT 0.216 43.632 248.617 43.728 ;
      RECT 0.216 44.400 248.617 44.496 ;
      RECT 0.216 45.168 248.617 45.264 ;
      RECT 0.216 45.936 248.617 46.032 ;
      RECT 0.216 46.704 248.617 46.800 ;
      RECT 0.216 47.472 248.617 47.568 ;
      RECT 0.216 48.240 248.617 48.336 ;
      RECT 0.216 49.008 248.617 49.104 ;
      RECT 0.216 49.776 248.617 49.872 ;
      RECT 0.216 50.544 248.617 50.640 ;
      RECT 0.216 51.312 248.617 51.408 ;
      RECT 0.216 52.080 248.617 52.176 ;
      RECT 0.216 52.848 248.617 52.944 ;
      RECT 0.216 53.616 248.617 53.712 ;
      RECT 0.216 54.384 248.617 54.480 ;
      RECT 0.216 55.152 248.617 55.248 ;
      RECT 0.216 55.920 248.617 56.016 ;
      RECT 0.216 56.688 248.617 56.784 ;
      RECT 0.216 57.456 248.617 57.552 ;
      RECT 0.216 58.224 248.617 58.320 ;
      RECT 0.216 58.992 248.617 59.088 ;
      RECT 0.216 59.760 248.617 59.856 ;
      RECT 0.216 60.528 248.617 60.624 ;
      RECT 0.216 61.296 248.617 61.392 ;
      RECT 0.216 62.064 248.617 62.160 ;
      RECT 0.216 62.832 248.617 62.928 ;
      RECT 0.216 63.600 248.617 63.696 ;
      RECT 0.216 64.368 248.617 64.464 ;
      RECT 0.216 65.136 248.617 65.232 ;
      RECT 0.216 65.904 248.617 66.000 ;
      RECT 0.216 66.672 248.617 66.768 ;
      RECT 0.216 67.440 248.617 67.536 ;
      RECT 0.216 68.208 248.617 68.304 ;
      RECT 0.216 68.976 248.617 69.072 ;
      RECT 0.216 69.744 248.617 69.840 ;
      RECT 0.216 70.512 248.617 70.608 ;
      RECT 0.216 71.280 248.617 71.376 ;
      RECT 0.216 72.048 248.617 72.144 ;
      RECT 0.216 72.816 248.617 72.912 ;
      RECT 0.216 73.584 248.617 73.680 ;
      RECT 0.216 74.352 248.617 74.448 ;
      RECT 0.216 75.120 248.617 75.216 ;
      RECT 0.216 75.888 248.617 75.984 ;
      RECT 0.216 76.656 248.617 76.752 ;
      RECT 0.216 77.424 248.617 77.520 ;
      RECT 0.216 78.192 248.617 78.288 ;
      RECT 0.216 78.960 248.617 79.056 ;
      RECT 0.216 79.728 248.617 79.824 ;
      RECT 0.216 80.496 248.617 80.592 ;
      RECT 0.216 81.264 248.617 81.360 ;
      RECT 0.216 82.032 248.617 82.128 ;
      RECT 0.216 82.800 248.617 82.896 ;
      RECT 0.216 83.568 248.617 83.664 ;
      RECT 0.216 84.336 248.617 84.432 ;
      RECT 0.216 85.104 248.617 85.200 ;
      RECT 0.216 85.872 248.617 85.968 ;
      RECT 0.216 86.640 248.617 86.736 ;
      RECT 0.216 87.408 248.617 87.504 ;
      RECT 0.216 88.176 248.617 88.272 ;
      RECT 0.216 88.944 248.617 89.040 ;
      RECT 0.216 89.712 248.617 89.808 ;
      RECT 0.216 90.480 248.617 90.576 ;
      RECT 0.216 91.248 248.617 91.344 ;
      RECT 0.216 92.016 248.617 92.112 ;
      RECT 0.216 92.784 248.617 92.880 ;
      RECT 0.216 93.552 248.617 93.648 ;
      RECT 0.216 94.320 248.617 94.416 ;
      RECT 0.216 95.088 248.617 95.184 ;
      RECT 0.216 95.856 248.617 95.952 ;
      RECT 0.216 96.624 248.617 96.720 ;
      RECT 0.216 97.392 248.617 97.488 ;
      RECT 0.216 98.160 248.617 98.256 ;
      RECT 0.216 98.928 248.617 99.024 ;
      RECT 0.216 99.696 248.617 99.792 ;
      RECT 0.216 100.464 248.617 100.560 ;
      RECT 0.216 101.232 248.617 101.328 ;
      RECT 0.216 102.000 248.617 102.096 ;
      RECT 0.216 102.768 248.617 102.864 ;
      RECT 0.216 103.536 248.617 103.632 ;
      RECT 0.216 104.304 248.617 104.400 ;
      RECT 0.216 105.072 248.617 105.168 ;
      RECT 0.216 105.840 248.617 105.936 ;
      RECT 0.216 106.608 248.617 106.704 ;
      RECT 0.216 107.376 248.617 107.472 ;
      RECT 0.216 108.144 248.617 108.240 ;
      RECT 0.216 108.912 248.617 109.008 ;
      RECT 0.216 109.680 248.617 109.776 ;
      RECT 0.216 110.448 248.617 110.544 ;
      RECT 0.216 111.216 248.617 111.312 ;
      RECT 0.216 111.984 248.617 112.080 ;
      RECT 0.216 112.752 248.617 112.848 ;
      RECT 0.216 113.520 248.617 113.616 ;
      RECT 0.216 114.288 248.617 114.384 ;
      RECT 0.216 115.056 248.617 115.152 ;
      RECT 0.216 115.824 248.617 115.920 ;
      RECT 0.216 116.592 248.617 116.688 ;
      RECT 0.216 117.360 248.617 117.456 ;
      RECT 0.216 118.128 248.617 118.224 ;
      RECT 0.216 118.896 248.617 118.992 ;
      RECT 0.216 119.664 248.617 119.760 ;
      RECT 0.216 120.432 248.617 120.528 ;
      RECT 0.216 121.200 248.617 121.296 ;
      RECT 0.216 121.968 248.617 122.064 ;
      RECT 0.216 122.736 248.617 122.832 ;
      RECT 0.216 123.504 248.617 123.600 ;
      RECT 0.216 124.272 248.617 124.368 ;
      RECT 0.216 125.040 248.617 125.136 ;
      RECT 0.216 125.808 248.617 125.904 ;
      RECT 0.216 126.576 248.617 126.672 ;
      RECT 0.216 127.344 248.617 127.440 ;
      RECT 0.216 128.112 248.617 128.208 ;
      RECT 0.216 128.880 248.617 128.976 ;
      RECT 0.216 129.648 248.617 129.744 ;
      RECT 0.216 130.416 248.617 130.512 ;
      RECT 0.216 131.184 248.617 131.280 ;
      RECT 0.216 131.952 248.617 132.048 ;
      RECT 0.216 132.720 248.617 132.816 ;
      RECT 0.216 133.488 248.617 133.584 ;
      RECT 0.216 134.256 248.617 134.352 ;
      RECT 0.216 135.024 248.617 135.120 ;
      RECT 0.216 135.792 248.617 135.888 ;
      RECT 0.216 136.560 248.617 136.656 ;
      RECT 0.216 137.328 248.617 137.424 ;
      RECT 0.216 138.096 248.617 138.192 ;
      RECT 0.216 138.864 248.617 138.960 ;
      RECT 0.216 139.632 248.617 139.728 ;
      RECT 0.216 140.400 248.617 140.496 ;
      RECT 0.216 141.168 248.617 141.264 ;
      RECT 0.216 141.936 248.617 142.032 ;
      RECT 0.216 142.704 248.617 142.800 ;
      RECT 0.216 143.472 248.617 143.568 ;
      RECT 0.216 144.240 248.617 144.336 ;
      RECT 0.216 145.008 248.617 145.104 ;
      RECT 0.216 145.776 248.617 145.872 ;
      RECT 0.216 146.544 248.617 146.640 ;
      RECT 0.216 147.312 248.617 147.408 ;
      RECT 0.216 148.080 248.617 148.176 ;
      RECT 0.216 148.848 248.617 148.944 ;
      RECT 0.216 149.616 248.617 149.712 ;
      RECT 0.216 150.384 248.617 150.480 ;
      RECT 0.216 151.152 248.617 151.248 ;
      RECT 0.216 151.920 248.617 152.016 ;
      RECT 0.216 152.688 248.617 152.784 ;
      RECT 0.216 153.456 248.617 153.552 ;
      RECT 0.216 154.224 248.617 154.320 ;
      RECT 0.216 154.992 248.617 155.088 ;
      RECT 0.216 155.760 248.617 155.856 ;
      RECT 0.216 156.528 248.617 156.624 ;
      RECT 0.216 157.296 248.617 157.392 ;
      RECT 0.216 158.064 248.617 158.160 ;
      RECT 0.216 158.832 248.617 158.928 ;
      RECT 0.216 159.600 248.617 159.696 ;
      RECT 0.216 160.368 248.617 160.464 ;
      RECT 0.216 161.136 248.617 161.232 ;
      RECT 0.216 161.904 248.617 162.000 ;
      RECT 0.216 162.672 248.617 162.768 ;
      RECT 0.216 163.440 248.617 163.536 ;
      RECT 0.216 164.208 248.617 164.304 ;
      RECT 0.216 164.976 248.617 165.072 ;
      RECT 0.216 165.744 248.617 165.840 ;
      RECT 0.216 166.512 248.617 166.608 ;
      RECT 0.216 167.280 248.617 167.376 ;
      RECT 0.216 168.048 248.617 168.144 ;
      RECT 0.216 168.816 248.617 168.912 ;
      RECT 0.216 169.584 248.617 169.680 ;
      RECT 0.216 170.352 248.617 170.448 ;
      RECT 0.216 171.120 248.617 171.216 ;
      RECT 0.216 171.888 248.617 171.984 ;
      RECT 0.216 172.656 248.617 172.752 ;
      RECT 0.216 173.424 248.617 173.520 ;
      RECT 0.216 174.192 248.617 174.288 ;
      RECT 0.216 174.960 248.617 175.056 ;
      RECT 0.216 175.728 248.617 175.824 ;
      RECT 0.216 176.496 248.617 176.592 ;
      RECT 0.216 177.264 248.617 177.360 ;
      RECT 0.216 178.032 248.617 178.128 ;
      RECT 0.216 178.800 248.617 178.896 ;
      RECT 0.216 179.568 248.617 179.664 ;
      RECT 0.216 180.336 248.617 180.432 ;
      RECT 0.216 181.104 248.617 181.200 ;
      RECT 0.216 181.872 248.617 181.968 ;
      RECT 0.216 182.640 248.617 182.736 ;
      RECT 0.216 183.408 248.617 183.504 ;
      RECT 0.216 184.176 248.617 184.272 ;
      RECT 0.216 184.944 248.617 185.040 ;
      RECT 0.216 185.712 248.617 185.808 ;
      RECT 0.216 186.480 248.617 186.576 ;
      RECT 0.216 187.248 248.617 187.344 ;
      RECT 0.216 188.016 248.617 188.112 ;
      RECT 0.216 188.784 248.617 188.880 ;
      RECT 0.216 189.552 248.617 189.648 ;
      RECT 0.216 190.320 248.617 190.416 ;
      RECT 0.216 191.088 248.617 191.184 ;
      RECT 0.216 191.856 248.617 191.952 ;
      RECT 0.216 192.624 248.617 192.720 ;
      RECT 0.216 193.392 248.617 193.488 ;
      RECT 0.216 194.160 248.617 194.256 ;
      RECT 0.216 194.928 248.617 195.024 ;
      RECT 0.216 195.696 248.617 195.792 ;
      RECT 0.216 196.464 248.617 196.560 ;
      RECT 0.216 197.232 248.617 197.328 ;
      RECT 0.216 198.000 248.617 198.096 ;
      RECT 0.216 198.768 248.617 198.864 ;
      RECT 0.216 199.536 248.617 199.632 ;
      RECT 0.216 200.304 248.617 200.400 ;
      RECT 0.216 201.072 248.617 201.168 ;
      RECT 0.216 201.840 248.617 201.936 ;
      RECT 0.216 202.608 248.617 202.704 ;
      RECT 0.216 203.376 248.617 203.472 ;
      RECT 0.216 204.144 248.617 204.240 ;
      RECT 0.216 204.912 248.617 205.008 ;
      RECT 0.216 205.680 248.617 205.776 ;
      RECT 0.216 206.448 248.617 206.544 ;
      RECT 0.216 207.216 248.617 207.312 ;
      RECT 0.216 207.984 248.617 208.080 ;
      RECT 0.216 208.752 248.617 208.848 ;
      RECT 0.216 209.520 248.617 209.616 ;
      RECT 0.216 210.288 248.617 210.384 ;
      RECT 0.216 211.056 248.617 211.152 ;
      RECT 0.216 211.824 248.617 211.920 ;
      RECT 0.216 212.592 248.617 212.688 ;
      RECT 0.216 213.360 248.617 213.456 ;
      RECT 0.216 214.128 248.617 214.224 ;
      RECT 0.216 214.896 248.617 214.992 ;
      RECT 0.216 215.664 248.617 215.760 ;
      RECT 0.216 216.432 248.617 216.528 ;
      RECT 0.216 217.200 248.617 217.296 ;
      RECT 0.216 217.968 248.617 218.064 ;
      RECT 0.216 218.736 248.617 218.832 ;
      RECT 0.216 219.504 248.617 219.600 ;
      RECT 0.216 220.272 248.617 220.368 ;
      RECT 0.216 221.040 248.617 221.136 ;
      RECT 0.216 221.808 248.617 221.904 ;
      RECT 0.216 222.576 248.617 222.672 ;
      RECT 0.216 223.344 248.617 223.440 ;
      RECT 0.216 224.112 248.617 224.208 ;
      RECT 0.216 224.880 248.617 224.976 ;
      RECT 0.216 225.648 248.617 225.744 ;
      RECT 0.216 226.416 248.617 226.512 ;
      RECT 0.216 227.184 248.617 227.280 ;
      RECT 0.216 227.952 248.617 228.048 ;
      RECT 0.216 228.720 248.617 228.816 ;
      RECT 0.216 229.488 248.617 229.584 ;
      RECT 0.216 230.256 248.617 230.352 ;
      RECT 0.216 231.024 248.617 231.120 ;
      RECT 0.216 231.792 248.617 231.888 ;
      RECT 0.216 232.560 248.617 232.656 ;
      RECT 0.216 233.328 248.617 233.424 ;
      RECT 0.216 234.096 248.617 234.192 ;
      RECT 0.216 234.864 248.617 234.960 ;
      RECT 0.216 235.632 248.617 235.728 ;
      RECT 0.216 236.400 248.617 236.496 ;
      RECT 0.216 237.168 248.617 237.264 ;
      RECT 0.216 237.936 248.617 238.032 ;
      RECT 0.216 238.704 248.617 238.800 ;
      RECT 0.216 239.472 248.617 239.568 ;
      RECT 0.216 240.240 248.617 240.336 ;
      RECT 0.216 241.008 248.617 241.104 ;
      RECT 0.216 241.776 248.617 241.872 ;
      RECT 0.216 242.544 248.617 242.640 ;
      RECT 0.216 243.312 248.617 243.408 ;
      RECT 0.216 244.080 248.617 244.176 ;
      RECT 0.216 244.848 248.617 244.944 ;
      RECT 0.216 245.616 248.617 245.712 ;
      RECT 0.216 246.384 248.617 246.480 ;
      RECT 0.216 247.152 248.617 247.248 ;
      RECT 0.216 247.920 248.617 248.016 ;
      RECT 0.216 248.688 248.617 248.784 ;
      RECT 0.216 249.456 248.617 249.552 ;
      RECT 0.216 250.224 248.617 250.320 ;
      RECT 0.216 250.992 248.617 251.088 ;
      RECT 0.216 251.760 248.617 251.856 ;
      RECT 0.216 252.528 248.617 252.624 ;
      RECT 0.216 253.296 248.617 253.392 ;
      RECT 0.216 254.064 248.617 254.160 ;
      RECT 0.216 254.832 248.617 254.928 ;
      RECT 0.216 255.600 248.617 255.696 ;
      RECT 0.216 256.368 248.617 256.464 ;
      RECT 0.216 257.136 248.617 257.232 ;
      RECT 0.216 257.904 248.617 258.000 ;
      RECT 0.216 258.672 248.617 258.768 ;
      RECT 0.216 259.440 248.617 259.536 ;
      RECT 0.216 260.208 248.617 260.304 ;
      RECT 0.216 260.976 248.617 261.072 ;
      RECT 0.216 261.744 248.617 261.840 ;
      RECT 0.216 262.512 248.617 262.608 ;
      RECT 0.216 263.280 248.617 263.376 ;
      RECT 0.216 264.048 248.617 264.144 ;
      RECT 0.216 264.816 248.617 264.912 ;
      RECT 0.216 265.584 248.617 265.680 ;
      RECT 0.216 266.352 248.617 266.448 ;
      RECT 0.216 267.120 248.617 267.216 ;
      RECT 0.216 267.888 248.617 267.984 ;
      RECT 0.216 268.656 248.617 268.752 ;
      RECT 0.216 269.424 248.617 269.520 ;
      RECT 0.216 270.192 248.617 270.288 ;
      RECT 0.216 270.960 248.617 271.056 ;
      RECT 0.216 271.728 248.617 271.824 ;
      RECT 0.216 272.496 248.617 272.592 ;
      RECT 0.216 273.264 248.617 273.360 ;
      RECT 0.216 274.032 248.617 274.128 ;
      RECT 0.216 274.800 248.617 274.896 ;
      RECT 0.216 275.568 248.617 275.664 ;
      RECT 0.216 276.336 248.617 276.432 ;
      RECT 0.216 277.104 248.617 277.200 ;
      RECT 0.216 277.872 248.617 277.968 ;
      RECT 0.216 278.640 248.617 278.736 ;
      RECT 0.216 279.408 248.617 279.504 ;
      RECT 0.216 280.176 248.617 280.272 ;
      RECT 0.216 280.944 248.617 281.040 ;
      RECT 0.216 281.712 248.617 281.808 ;
      RECT 0.216 282.480 248.617 282.576 ;
      RECT 0.216 283.248 248.617 283.344 ;
      RECT 0.216 284.016 248.617 284.112 ;
      RECT 0.216 284.784 248.617 284.880 ;
      RECT 0.216 285.552 248.617 285.648 ;
      RECT 0.216 286.320 248.617 286.416 ;
      RECT 0.216 287.088 248.617 287.184 ;
      RECT 0.216 287.856 248.617 287.952 ;
      RECT 0.216 288.624 248.617 288.720 ;
      RECT 0.216 289.392 248.617 289.488 ;
      RECT 0.216 290.160 248.617 290.256 ;
      RECT 0.216 290.928 248.617 291.024 ;
      RECT 0.216 291.696 248.617 291.792 ;
      RECT 0.216 292.464 248.617 292.560 ;
      RECT 0.216 293.232 248.617 293.328 ;
      RECT 0.216 294.000 248.617 294.096 ;
      RECT 0.216 294.768 248.617 294.864 ;
      RECT 0.216 295.536 248.617 295.632 ;
      RECT 0.216 296.304 248.617 296.400 ;
      RECT 0.216 297.072 248.617 297.168 ;
      RECT 0.216 297.840 248.617 297.936 ;
      RECT 0.216 298.608 248.617 298.704 ;
      RECT 0.216 299.376 248.617 299.472 ;
      RECT 0.216 300.144 248.617 300.240 ;
      RECT 0.216 300.912 248.617 301.008 ;
      RECT 0.216 301.680 248.617 301.776 ;
      RECT 0.216 302.448 248.617 302.544 ;
      RECT 0.216 303.216 248.617 303.312 ;
      RECT 0.216 303.984 248.617 304.080 ;
      RECT 0.216 304.752 248.617 304.848 ;
      RECT 0.216 305.520 248.617 305.616 ;
      RECT 0.216 306.288 248.617 306.384 ;
      RECT 0.216 307.056 248.617 307.152 ;
      RECT 0.216 307.824 248.617 307.920 ;
      RECT 0.216 308.592 248.617 308.688 ;
      RECT 0.216 309.360 248.617 309.456 ;
      RECT 0.216 310.128 248.617 310.224 ;
      RECT 0.216 310.896 248.617 310.992 ;
    END
  END VDD
  OBS
    LAYER M1 ;
    RECT 0 0 248.833 311.040 ;
    LAYER M2 ;
    RECT 0 0 248.833 311.040 ;
    LAYER M3 ;
    RECT 0 0 248.833 311.040 ;
    LAYER M4 ;
    RECT 0 0 248.833 311.040 ;
  END
END fakeram_w16_l8192

END LIBRARY
